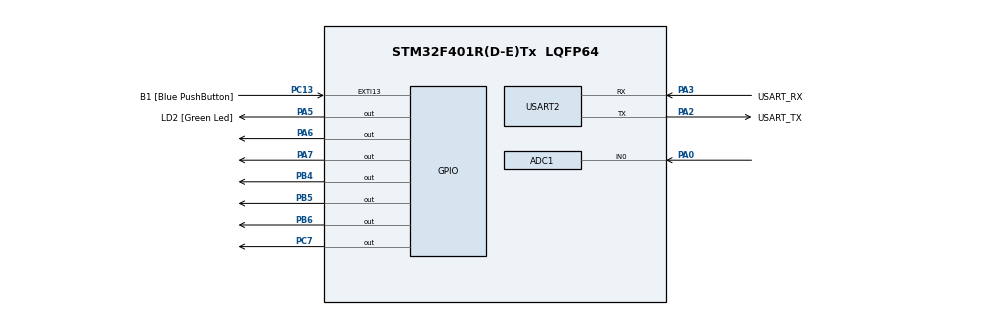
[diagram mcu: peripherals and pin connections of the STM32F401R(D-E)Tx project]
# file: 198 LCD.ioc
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ADC1.Channel-0\#ChannelRegularConversion=ADC_CHANNEL_0
ADC1.NbrOfConversionFlag=1
ADC1.Rank-0\#ChannelRegularConversion=1
ADC1.SamplingTime-0\#ChannelRegularConversion=ADC_SAMPLETIME_3CYCLES
ADC1.master=1
Mcu.Family=STM32F4
Mcu.Name=STM32F401R(D-E)Tx
Mcu.Package=LQFP64
NVIC.PriorityGroup=NVIC_PRIORITYGROUP_0
PA0-WKUP.Signal=ADCx_IN0
PA13.GPIO_Label=TMS
PA13.Mode=Serial_Wire
PA13.Signal=SYS_JTMS-SWDIO
PA14.GPIO_Label=TCK
PA14.Mode=Serial_Wire
PA14.Signal=SYS_JTCK-SWCLK
PA2.GPIO_Label=USART_TX
PA2.GPIO_Mode=GPIO_MODE_AF_PP
PA2.GPIO_PuPd=GPIO_NOPULL
PA2.GPIO_Speed=GPIO_SPEED_FREQ_LOW
PA2.Mode=Asynchronous
PA2.Signal=USART2_TX
PA3.GPIO_Label=USART_RX
PA3.GPIO_Mode=GPIO_MODE_AF_PP
PA3.GPIO_PuPd=GPIO_NOPULL
PA3.GPIO_Speed=GPIO_SPEED_FREQ_LOW
PA3.Mode=Asynchronous
PA3.Signal=USART2_RX
PA5.GPIO_Label=LD2 [Green Led]
PA5.GPIO_Mode=GPIO_MODE_OUTPUT_PP
PA5.GPIO_PuPd=GPIO_NOPULL
PA5.GPIO_Speed=GPIO_SPEED_FREQ_LOW
PA5.Signal=GPIO_Output
PA6.Signal=GPIO_Output
PA7.Signal=GPIO_Output
PB3.GPIO_Label=SWO
PB3.Signal=SYS_JTDO-SWO
PB4.Signal=GPIO_Output
PB5.Signal=GPIO_Output
PB6.Signal=GPIO_Output
PC13-ANTI_TAMP.GPIO_Label=B1 [Blue PushButton]
PC13-ANTI_TAMP.GPIO_ModeDefaultEXTI=GPIO_MODE_IT_FALLING
PC13-ANTI_TAMP.GPIO_PuPd=GPIO_NOPULL
PC13-ANTI_TAMP.Signal=GPXTI13
PC14-OSC32_IN.Mode=LSE-External-Oscillator
PC14-OSC32_IN.Signal=RCC_OSC32_IN
PC15-OSC32_OUT.Mode=LSE-External-Oscillator
PC15-OSC32_OUT.Signal=RCC_OSC32_OUT
PC7.Signal=GPIO_Output
PH0\ -\ OSC_IN.Mode=HSE-External-Clock-Source
PH0\ -\ OSC_IN.Signal=RCC_OSC_IN
PH1\ -\ OSC_OUT.Mode=HSE-External-Clock-Source
PH1\ -\ OSC_OUT.Signal=RCC_OSC_OUT
ProjectManager.HeapSize=0x200
ProjectManager.StackSize=0x400
ProjectManager.TargetToolchain=STM32CubeIDE
RCC.48MHZClocksFreq_Value=20571428.57142857
RCC.AHBFreq_Value=72000000
RCC.APB1CLKDivider=RCC_HCLK_DIV2
RCC.APB1Freq_Value=36000000
RCC.APB1TimFreq_Value=72000000
RCC.APB2Freq_Value=72000000
RCC.APB2TimFreq_Value=72000000
RCC.CortexFreq_Value=72000000
RCC.HCLKFreq_Value=72000000
RCC.HSE_VALUE=8000000
RCC.HSI_VALUE=16000000
RCC.PLLM=8
RCC.PLLN=72
RCC.PLLQ=7
RCC.SYSCLKFreq_VALUE=72000000
RCC.SYSCLKSource=RCC_SYSCLKSOURCE_PLLCLK
RCC.VCOOutputFreq_Value=144000000
SH.ADCx_IN0.0=ADC1_IN0,IN0
USART2.VirtualMode=VM_ASYNC
board=NUCLEO-F401RE

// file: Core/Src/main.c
/* USER CODE BEGIN Header */
/**
  ******************************************************************************
  * @file           : main.c
  * @brief          : Main program body
  ******************************************************************************
  * @attention
  *
  * Copyright (c) 2023 STMicroelectronics.
  * All rights reserved.
  *
  * This software is licensed under terms that can be found in the LICENSE file
  * in the root directory of this software component.
  * If no LICENSE file comes with this software, it is provided AS-IS.
  *
  ******************************************************************************
  */
/* USER CODE END Header */
#include "main.h"

/* USER CODE BEGIN Includes */
#include "mae.h"

/* USER CODE END Includes */

ADC_HandleTypeDef hadc1;
uint16_t adcValue = 0;

UART_HandleTypeDef huart2;

void SystemClock_Config(void);
static void MX_GPIO_Init(void);
static void MX_USART2_UART_Init(void);
static void MX_ADC1_Init(void);
int convertToHeartRate(uint16_t adcValue);

int main(void)
{

  /* MCU Configuration--------------------------------------------------------*/

  /* Reset of all peripherals, Initializes the Flash interface and the Systick. */
  HAL_Init();

  /* Configure the system clock */
  SystemClock_Config();

  /* Initialize all configured peripherals */
  MX_GPIO_Init();
  MX_USART2_UART_Init();
  MX_ADC1_Init();
  /* USER CODE BEGIN 2 */
  // Lcd_PortType ports[] = { D4_GPIO_Port, D5_GPIO_Port, D6_GPIO_Port, D7_GPIO_Port };
  Lcd_PortType ports[] = { GPIOC, GPIOB, GPIOA, GPIOA };
  // Lcd_PinType pins[] = {D4_Pin, D5_Pin, D6_Pin, D7_Pin};
  Lcd_PinType pins[] = {GPIO_PIN_7, GPIO_PIN_6, GPIO_PIN_7, GPIO_PIN_6};
  Lcd_HandleTypeDef lcd;
  // Lcd_create(ports, pins, RS_GPIO_Port, RS_Pin, EN_GPIO_Port, EN_Pin, LCD_4_BIT_MODE);
  lcd = Lcd_create(ports, pins, GPIOB, GPIO_PIN_5, GPIOB, GPIO_PIN_4, LCD_4_BIT_MODE);

  /*  for ( int x = 1; x <= 200 ; x++ ){
      Lcd_cursor(&lcd, 1, 7);
      Lcd_int(&lcd, x);
      HAL_Delay (1000);
    }*/
    MX_ADC1_Init();
  /* USER CODE END 2 */

  /* Infinite loop */
  /* USER CODE BEGIN WHILE */
    while (1)
    {
    Lcd_clear(&lcd);

    Lcd_cursor(&lcd, 0, 1);
    Lcd_string(&lcd, "Heart Rate: ");
      HAL_ADC_Start(&hadc1);
      HAL_ADC_PollForConversion(&hadc1, HAL_MAX_DELAY);
      adcValue = HAL_ADC_GetValue(&hadc1);

      // Convert ADC value to heart rate (adjust this based on sensor characteristics)
      int heartRate = convertToHeartRate(adcValue);

      // Display the heart rate on the LCD
      Lcd_cursor(&lcd, 1, 7);
      Lcd_int(&lcd, heartRate);

      // Delay or other processing...
      HAL_Delay(1000);//changed from 1000 to 1500
    }
  }

int convertToHeartRate(uint16_t adcValue)
{
  // Example conversion, adjust based on sensor characteristics
  // This is a simple linear conversion for demonstration purposes
  // You need to calibrate this based on your sensor's behavior
  int heartRate = (adcValue * 100) / 4095;

  return heartRate;
}

void SystemClock_Config(void)
{
  RCC_OscInitTypeDef RCC_OscInitStruct = {0};
  RCC_ClkInitTypeDef RCC_ClkInitStruct = {0};

  /** Configure the main internal regulator output voltage
  */
  __HAL_RCC_PWR_CLK_ENABLE();
  __HAL_PWR_VOLTAGESCALING_CONFIG(PWR_REGULATOR_VOLTAGE_SCALE2);

  /** Initializes the RCC Oscillators according to the specified parameters
  * in the RCC_OscInitTypeDef structure.
  */
  RCC_OscInitStruct.OscillatorType = RCC_OSCILLATORTYPE_HSI;
  RCC_OscInitStruct.HSIState = RCC_HSI_ON;
  RCC_OscInitStruct.HSICalibrationValue = RCC_HSICALIBRATION_DEFAULT;
  RCC_OscInitStruct.PLL.PLLState = RCC_PLL_ON;
  RCC_OscInitStruct.PLL.PLLSource = RCC_PLLSOURCE_HSI;
  RCC_OscInitStruct.PLL.PLLM = 16;
  RCC_OscInitStruct.PLL.PLLN = 336;
  RCC_OscInitStruct.PLL.PLLP = RCC_PLLP_DIV4;
  RCC_OscInitStruct.PLL.PLLQ = 7;
  if (HAL_RCC_OscConfig(&RCC_OscInitStruct) != HAL_OK)
  {
    Error_Handler();
  }

  /** Initializes the CPU, AHB and APB buses clocks
  */
  RCC_ClkInitStruct.ClockType = RCC_CLOCKTYPE_HCLK|RCC_CLOCKTYPE_SYSCLK
                              |RCC_CLOCKTYPE_PCLK1|RCC_CLOCKTYPE_PCLK2;
  RCC_ClkInitStruct.SYSCLKSource = RCC_SYSCLKSOURCE_PLLCLK;
  RCC_ClkInitStruct.AHBCLKDivider = RCC_SYSCLK_DIV1;
  RCC_ClkInitStruct.APB1CLKDivider = RCC_HCLK_DIV2;
  RCC_ClkInitStruct.APB2CLKDivider = RCC_HCLK_DIV1;

  if (HAL_RCC_ClockConfig(&RCC_ClkInitStruct, FLASH_LATENCY_2) != HAL_OK)
  {
    Error_Handler();
  }
}

static void MX_ADC1_Init(void)
{

  ADC_ChannelConfTypeDef sConfig = {0};

  /** Configure the global features of the ADC (Clock, Resolution, Data Alignment and number of conversion)
  */
  hadc1.Instance = ADC1;
  hadc1.Init.ClockPrescaler = ADC_CLOCK_SYNC_PCLK_DIV4;
  hadc1.Init.Resolution = ADC_RESOLUTION_12B;
  hadc1.Init.ScanConvMode = DISABLE;
  hadc1.Init.ContinuousConvMode = DISABLE;
  hadc1.Init.DiscontinuousConvMode = DISABLE;
  hadc1.Init.ExternalTrigConvEdge = ADC_EXTERNALTRIGCONVEDGE_NONE;
  hadc1.Init.ExternalTrigConv = ADC_SOFTWARE_START;
  hadc1.Init.DataAlign = ADC_DATAALIGN_RIGHT;
  hadc1.Init.NbrOfConversion = 1;
  hadc1.Init.DMAContinuousRequests = DISABLE;
  hadc1.Init.EOCSelection = ADC_EOC_SINGLE_CONV;
  if (HAL_ADC_Init(&hadc1) != HAL_OK)
  {
    Error_Handler();
  }

  /** Configure for the selected ADC regular channel its corresponding rank in the sequencer and its sample time.
  */
  sConfig.Channel = ADC_CHANNEL_0;
  sConfig.Rank = 1;
  sConfig.SamplingTime = ADC_SAMPLETIME_3CYCLES;
  if (HAL_ADC_ConfigChannel(&hadc1, &sConfig) != HAL_OK)
  {
    Error_Handler();
  }

}

static void MX_USART2_UART_Init(void)
{

  huart2.Instance = USART2;
  huart2.Init.BaudRate = 115200;
  huart2.Init.WordLength = UART_WORDLENGTH_8B;
  huart2.Init.StopBits = UART_STOPBITS_1;
  huart2.Init.Parity = UART_PARITY_NONE;
  huart2.Init.Mode = UART_MODE_TX_RX;
  huart2.Init.HwFlowCtl = UART_HWCONTROL_NONE;
  huart2.Init.OverSampling = UART_OVERSAMPLING_16;
  if (HAL_UART_Init(&huart2) != HAL_OK)
  {
    Error_Handler();
  }

}

static void MX_GPIO_Init(void)
{
  GPIO_InitTypeDef GPIO_InitStruct = {0};

  /* GPIO Ports Clock Enable */
  __HAL_RCC_GPIOC_CLK_ENABLE();
  __HAL_RCC_GPIOH_CLK_ENABLE();
  __HAL_RCC_GPIOA_CLK_ENABLE();
  __HAL_RCC_GPIOB_CLK_ENABLE();

  /*Configure GPIO pin Output Level */
  HAL_GPIO_WritePin(GPIOA, LD2_Pin|GPIO_PIN_6|GPIO_PIN_7, GPIO_PIN_RESET);

  /*Configure GPIO pin Output Level */
  HAL_GPIO_WritePin(GPIOC, GPIO_PIN_7, GPIO_PIN_RESET);

  /*Configure GPIO pin Output Level */
  HAL_GPIO_WritePin(GPIOB, GPIO_PIN_4|GPIO_PIN_5|GPIO_PIN_6, GPIO_PIN_RESET);

  /*Configure GPIO pin : B1_Pin */
  GPIO_InitStruct.Pin = B1_Pin;
  GPIO_InitStruct.Mode = GPIO_MODE_IT_FALLING;
  GPIO_InitStruct.Pull = GPIO_NOPULL;
  HAL_GPIO_Init(B1_GPIO_Port, &GPIO_InitStruct);

  /*Configure GPIO pins : LD2_Pin PA6 PA7 */
  GPIO_InitStruct.Pin = LD2_Pin|GPIO_PIN_6|GPIO_PIN_7;
  GPIO_InitStruct.Mode = GPIO_MODE_OUTPUT_PP;
  GPIO_InitStruct.Pull = GPIO_NOPULL;
  GPIO_InitStruct.Speed = GPIO_SPEED_FREQ_LOW;
  HAL_GPIO_Init(GPIOA, &GPIO_InitStruct);

  /*Configure GPIO pin : PC7 */
  GPIO_InitStruct.Pin = GPIO_PIN_7;
  GPIO_InitStruct.Mode = GPIO_MODE_OUTPUT_PP;
  GPIO_InitStruct.Pull = GPIO_NOPULL;
  GPIO_InitStruct.Speed = GPIO_SPEED_FREQ_LOW;
  HAL_GPIO_Init(GPIOC, &GPIO_InitStruct);

  /*Configure GPIO pins : PB4 PB5 PB6 */
  GPIO_InitStruct.Pin = GPIO_PIN_4|GPIO_PIN_5|GPIO_PIN_6;
  GPIO_InitStruct.Mode = GPIO_MODE_OUTPUT_PP;
  GPIO_InitStruct.Pull = GPIO_NOPULL;
  GPIO_InitStruct.Speed = GPIO_SPEED_FREQ_LOW;
  HAL_GPIO_Init(GPIOB, &GPIO_InitStruct);

}

void Error_Handler(void)
{
  __disable_irq();
  while (1)
  {
  }
}
